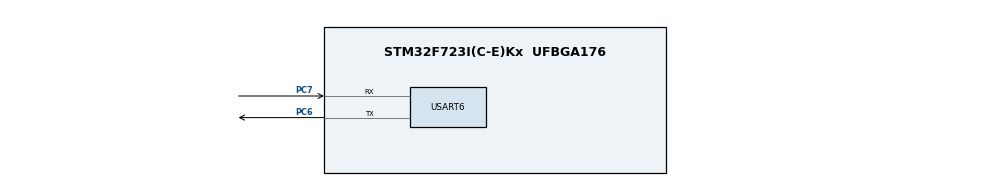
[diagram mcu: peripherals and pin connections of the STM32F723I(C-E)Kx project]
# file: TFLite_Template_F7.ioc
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CORTEX_M7.CPU_DCache=Enabled
CORTEX_M7.CPU_ICache=Enabled
Mcu.Family=STM32F7
Mcu.Name=STM32F723I(C-E)Kx
Mcu.Package=UFBGA176
NVIC.PriorityGroup=NVIC_PRIORITYGROUP_4
PC6.Mode=Asynchronous
PC6.Signal=USART6_TX
PC7.Mode=Asynchronous
PC7.Signal=USART6_RX
ProjectManager.HeapSize=0x200
ProjectManager.StackSize=0x400
ProjectManager.TargetToolchain=STM32CubeIDE
RCC.HSE_VALUE=25000000
RCC.HSI_VALUE=16000000
RCC.LSE_VALUE=32768
RCC.USBFreq_Value=96000000
RCC.VCOOutputFreq_Value=192000000
STMicroelectronics.X-CUBE-AI.5.0.0.ActivationBufferSizeList=13520
STMicroelectronics.X-CUBE-AI.5.0.0.ApplicationCcArtificialOoIntelligenceJjApplication=ApplicationTemplate
STMicroelectronics.X-CUBE-AI.5.0.0.HeapSize=0x200
STMicroelectronics.X-CUBE-AI.5.0.0.InternalRamActivationBufferMaxSize=AI_NETWORK_DATA_ACTIVATIONS_SIZE
STMicroelectronics.X-CUBE-AI.5.0.0.LatestDirectoryUsed-1bc099311d817547b312fa381c9899bdb5237f95033466fcd13645941940d504=C\:\\Users\\Marco\\Documents\\GitHub\\Embedded-neural-net-traffic-sign-recognition\\Models
STMicroelectronics.X-CUBE-AI.5.0.0.MaximumNumberOfInputLayer=1
STMicroelectronics.X-CUBE-AI.5.0.0.MaximumNumberOfOutputLayer=1
STMicroelectronics.X-CUBE-AI.5.0.0.MaximumSizeOfInputLayer=4096
STMicroelectronics.X-CUBE-AI.5.0.0.MaximumSizeOfOutputLayer=172
STMicroelectronics.X-CUBE-AI.5.0.0.ModelActualCompression-1bc099311d817547b312fa381c9899bdb5237f95033466fcd13645941940d504=0.0
STMicroelectronics.X-CUBE-AI.5.0.0.ModelFlashOccupation-1bc099311d817547b312fa381c9899bdb5237f95033466fcd13645941940d504=104808
STMicroelectronics.X-CUBE-AI.5.0.0.ModelHashList=1bc099311d817547b312fa381c9899bdb5237f95033466fcd13645941940d504
STMicroelectronics.X-CUBE-AI.5.0.0.ModelKind-1bc099311d817547b312fa381c9899bdb5237f95033466fcd13645941940d504=TFLITE
STMicroelectronics.X-CUBE-AI.5.0.0.ModelMacc-1bc099311d817547b312fa381c9899bdb5237f95033466fcd13645941940d504=1498879
STMicroelectronics.X-CUBE-AI.5.0.0.ModelName-1bc099311d817547b312fa381c9899bdb5237f95033466fcd13645941940d504=network
STMicroelectronics.X-CUBE-AI.5.0.0.ModelNameList=network
STMicroelectronics.X-CUBE-AI.5.0.0.ModelRamOccupation-1bc099311d817547b312fa381c9899bdb5237f95033466fcd13645941940d504=13520
STMicroelectronics.X-CUBE-AI.5.0.0.ModelStructureFile-1bc099311d817547b312fa381c9899bdb5237f95033466fcd13645941940d504=C\:\\Users\\Marco\\Documents\\GitHub\\Embedded-neural-net-traffic-sign-recognition\\Models\\model_pq_w.tflite
STMicroelectronics.X-CUBE-AI.5.0.0.ModelType-1bc099311d817547b312fa381c9899bdb5237f95033466fcd13645941940d504=Saved model
STMicroelectronics.X-CUBE-AI.5.0.0.NNModelInformation_AchievedCompression-1bc099311d817547b312fa381c9899bdb5237f95033466fcd13645941940d504=0.0
STMicroelectronics.X-CUBE-AI.5.0.0.NNModelInformation_CompressionFactor-1bc099311d817547b312fa381c9899bdb5237f95033466fcd13645941940d504=0.004658653016621614
STMicroelectronics.X-CUBE-AI.5.0.0.NNModelInformation_EvaluationStatus-1bc099311d817547b312fa381c9899bdb5237f95033466fcd13645941940d504=NOT EVALUATED
STMicroelectronics.X-CUBE-AI.5.0.0.NNModelInformation_HeapSizeNeeded-1bc099311d817547b312fa381c9899bdb5237f95033466fcd13645941940d504=4096
STMicroelectronics.X-CUBE-AI.5.0.0.NNModelInformation_ModelInSizeByName-1bc099311d817547b312fa381c9899bdb5237f95033466fcd13645941940d504={input_0\=4096}
STMicroelectronics.X-CUBE-AI.5.0.0.NNModelInformation_ModelMacc-1bc099311d817547b312fa381c9899bdb5237f95033466fcd13645941940d504=1498879
STMicroelectronics.X-CUBE-AI.5.0.0.NNModelInformation_ModelName-1bc099311d817547b312fa381c9899bdb5237f95033466fcd13645941940d504=network
STMicroelectronics.X-CUBE-AI.5.0.0.NNModelInformation_ModelOutSizeByName-1bc099311d817547b312fa381c9899bdb5237f95033466fcd13645941940d504={nl_15\=172}
STMicroelectronics.X-CUBE-AI.5.0.0.NNModelInformation_ModelRam-1bc099311d817547b312fa381c9899bdb5237f95033466fcd13645941940d504=13520
STMicroelectronics.X-CUBE-AI.5.0.0.NNModelInformation_ModelRom-1bc099311d817547b312fa381c9899bdb5237f95033466fcd13645941940d504=104808
STMicroelectronics.X-CUBE-AI.5.0.0.NNModelInformation_ModelSize-1bc099311d817547b312fa381c9899bdb5237f95033466fcd13645941940d504=104322
STMicroelectronics.X-CUBE-AI.5.0.0.NNModelInformation_NbOfParameters-1bc099311d817547b312fa381c9899bdb5237f95033466fcd13645941940d504=103413
STMicroelectronics.X-CUBE-AI.5.0.0.StackSize=0x400
STMicroelectronics.X-CUBE-AI.5.0.0.WorkingBufferStartAddrList=0xFFFFFFFF
STMicroelectronics.X-CUBE-AI.5.0.0.XAaCUBEAaAICcArtificialOoIntelligenceJjCore=true
USART6.VirtualMode-Asynchronous=VM_ASYNC
VP_CRC_VS_CRC.Mode=CRC_Activate
VP_STMicroelectronics.X-CUBE-AI_VS_ArtificialOoIntelligenceJjApplication_5.0.0.Mode=ArtificialOoIntelligenceJjApplication
VP_STMicroelectronics.X-CUBE-AI_VS_ArtificialOoIntelligenceJjXAaCUBEAaAI_5.0.0.Mode=ArtificialOoIntelligenceJjXAaCUBEAaAI
board=custom

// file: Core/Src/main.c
/* USER CODE BEGIN Header */
/**
  ******************************************************************************
  * @file           : main.c
  * @brief          : Main program body
  ******************************************************************************
  * @attention
  *
  * <h2><center>&copy; Copyright (c) 2020 STMicroelectronics.
  * All rights reserved.</center></h2>
  *
  * This software component is licensed by ST under BSD 3-Clause license,
  * the "License"; You may not use this file except in compliance with the
  * License. You may obtain a copy of the License at:
  *                        opensource.org/licenses/BSD-3-Clause
  *
  ******************************************************************************
  */
/* USER CODE END Header */

#include "main.h"
#include "app_x-cube-ai.h"

/* USER CODE BEGIN PTD */
#define BUFFER_SIZE 1024
/* USER CODE END PTD */

CRC_HandleTypeDef hcrc;

UART_HandleTypeDef huart6;

void SystemClock_Config(void);
static void MX_GPIO_Init(void);
static void MX_USART6_UART_Init(void);
static void MX_CRC_Init(void);

int main(void)
{

  /* Enable I-Cache---------------------------------------------------------*/
  SCB_EnableICache();

  /* Enable D-Cache---------------------------------------------------------*/
  SCB_EnableDCache();

  /* MCU Configuration--------------------------------------------------------*/

  /* Reset of all peripherals, Initializes the Flash interface and the Systick. */
  HAL_Init();

  /* Configure the system clock */
  SystemClock_Config();

  /* Initialize all configured peripherals */
  MX_GPIO_Init();
  MX_USART6_UART_Init();
  MX_CRC_Init();
  MX_X_CUBE_AI_Init();
  /* USER CODE BEGIN 2 */
  //char buffer[50] = {};
  //sprintf(buffer, "Starting the App\n");
  //HAL_UART_Transmit(&huart6, buffer, strlen(buffer), 1000);

  uint8_t x_data[BUFFER_SIZE] = {};
    float output_arr[43] = {};
    int array_pos = 0;
    uint8_t byte_received = 0;

  /* USER CODE END 2 */

  /* Infinite loop */
  while (1)
  {

  //MX_X_CUBE_AI_Process();
    /* USER CODE BEGIN 3 */
	  int uart_status = HAL_UART_Receive(&huart6, &byte_received, sizeof(uint8_t), 100);
	  	  if (uart_status == HAL_OK)
	  	  {
	  	  	x_data[array_pos] = byte_received;
	  	  	array_pos++;
	  	  }
	  	  if (array_pos == BUFFER_SIZE)
	  	  {
	  	  	//HAL_Delay(500);
	  	  	//HAL_UART_Transmit(&huart1, x_data, BUFFER_SIZE*sizeof(uint8_t), 2000);
	  	  	array_pos = 0;

	  	  	// instantiate float array
	  	  	float fArray[BUFFER_SIZE];

	  	  	// step through each element of integer array, and copy into float array as float
	  	  	for (int i = 0; i < BUFFER_SIZE; i++)
	  	  	{
	  	  		fArray[i] = ((float)x_data[i]) / 255;
	  	  	}

	  	  	ai_i8 x_data_ai[4 * BUFFER_SIZE] = {};
	  	  	ai_i8 y_data_ai[4 * 43] = {};
	  	  	uint8_t best_output = 0;
	  	  	float accuracy = 0;
	  	  	memcpy(x_data_ai, fArray, 4 * BUFFER_SIZE);

	  	  	ResetTimer();
	  	  	StartTimer();
	  	  	aiRun(x_data_ai, y_data_ai);
	  	  	StopTimer();
	  	  	uint32_t cycles_count = getCycles();
	  	  	memcpy(output_arr, y_data_ai, sizeof(float) * 43);
	  	  	for (int i = 0; i < 43; i++)
	  	  	{
	  	  		if (accuracy < output_arr[i])
	  	  		{
	  	  			accuracy = output_arr[i];
	  	  			best_output = i;
	  	  		}
	  	  	}
	  	  	HAL_UART_Transmit(&huart6, &best_output, 1, 200);
	  	  	HAL_UART_Transmit(&huart6, &accuracy, sizeof(float), 200);
	  	  	HAL_UART_Transmit(&huart6, &cycles_count, sizeof(uint32_t), 200);
	  	  }
  }
  /* USER CODE END 3 */
}

void SystemClock_Config(void)
{
  RCC_OscInitTypeDef RCC_OscInitStruct = {0};
  RCC_ClkInitTypeDef RCC_ClkInitStruct = {0};
  RCC_PeriphCLKInitTypeDef PeriphClkInitStruct = {0};

  /** Configure the main internal regulator output voltage
  */
  __HAL_RCC_PWR_CLK_ENABLE();
  __HAL_PWR_VOLTAGESCALING_CONFIG(PWR_REGULATOR_VOLTAGE_SCALE1);
  /** Initializes the CPU, AHB and APB busses clocks
  */
  RCC_OscInitStruct.OscillatorType = RCC_OSCILLATORTYPE_HSI;
  RCC_OscInitStruct.HSIState = RCC_HSI_ON;
  RCC_OscInitStruct.HSICalibrationValue = RCC_HSICALIBRATION_DEFAULT;
  RCC_OscInitStruct.PLL.PLLState = RCC_PLL_ON;
  RCC_OscInitStruct.PLL.PLLSource = RCC_PLLSOURCE_HSI;
  RCC_OscInitStruct.PLL.PLLM = 8;
  RCC_OscInitStruct.PLL.PLLN = 216;
  RCC_OscInitStruct.PLL.PLLP = RCC_PLLP_DIV2;
  RCC_OscInitStruct.PLL.PLLQ = 2;
  if (HAL_RCC_OscConfig(&RCC_OscInitStruct) != HAL_OK)
  {
    Error_Handler();
  }
  /** Activate the Over-Drive mode
  */
  if (HAL_PWREx_EnableOverDrive() != HAL_OK)
  {
    Error_Handler();
  }
  /** Initializes the CPU, AHB and APB busses clocks
  */
  RCC_ClkInitStruct.ClockType = RCC_CLOCKTYPE_HCLK|RCC_CLOCKTYPE_SYSCLK
                              |RCC_CLOCKTYPE_PCLK1|RCC_CLOCKTYPE_PCLK2;
  RCC_ClkInitStruct.SYSCLKSource = RCC_SYSCLKSOURCE_PLLCLK;
  RCC_ClkInitStruct.AHBCLKDivider = RCC_SYSCLK_DIV1;
  RCC_ClkInitStruct.APB1CLKDivider = RCC_HCLK_DIV4;
  RCC_ClkInitStruct.APB2CLKDivider = RCC_HCLK_DIV2;

  if (HAL_RCC_ClockConfig(&RCC_ClkInitStruct, FLASH_LATENCY_7) != HAL_OK)
  {
    Error_Handler();
  }
  PeriphClkInitStruct.PeriphClockSelection = RCC_PERIPHCLK_USART6;
  PeriphClkInitStruct.Usart6ClockSelection = RCC_USART6CLKSOURCE_PCLK2;
  if (HAL_RCCEx_PeriphCLKConfig(&PeriphClkInitStruct) != HAL_OK)
  {
    Error_Handler();
  }
}

static void MX_CRC_Init(void)
{

  hcrc.Instance = CRC;
  hcrc.Init.DefaultPolynomialUse = DEFAULT_POLYNOMIAL_ENABLE;
  hcrc.Init.DefaultInitValueUse = DEFAULT_INIT_VALUE_ENABLE;
  hcrc.Init.InputDataInversionMode = CRC_INPUTDATA_INVERSION_NONE;
  hcrc.Init.OutputDataInversionMode = CRC_OUTPUTDATA_INVERSION_DISABLE;
  hcrc.InputDataFormat = CRC_INPUTDATA_FORMAT_BYTES;
  if (HAL_CRC_Init(&hcrc) != HAL_OK)
  {
    Error_Handler();
  }

}

static void MX_USART6_UART_Init(void)
{

  huart6.Instance = USART6;
  huart6.Init.BaudRate = 115200;
  huart6.Init.WordLength = UART_WORDLENGTH_8B;
  huart6.Init.StopBits = UART_STOPBITS_1;
  huart6.Init.Parity = UART_PARITY_NONE;
  huart6.Init.Mode = UART_MODE_TX_RX;
  huart6.Init.HwFlowCtl = UART_HWCONTROL_NONE;
  huart6.Init.OverSampling = UART_OVERSAMPLING_16;
  huart6.Init.OneBitSampling = UART_ONE_BIT_SAMPLE_DISABLE;
  huart6.AdvancedInit.AdvFeatureInit = UART_ADVFEATURE_NO_INIT;
  if (HAL_UART_Init(&huart6) != HAL_OK)
  {
    Error_Handler();
  }

}

static void MX_GPIO_Init(void)
{

  /* GPIO Ports Clock Enable */
  __HAL_RCC_GPIOC_CLK_ENABLE();

}

void Error_Handler(void)
{
}

/************************ (C) COPYRIGHT STMicroelectronics *****END OF FILE****/
